VERSION 5.7 ;
  NOWIREEXTENSIONATPIN ON ;
  DIVIDERCHAR "/" ;
  BUSBITCHARS "[]" ;
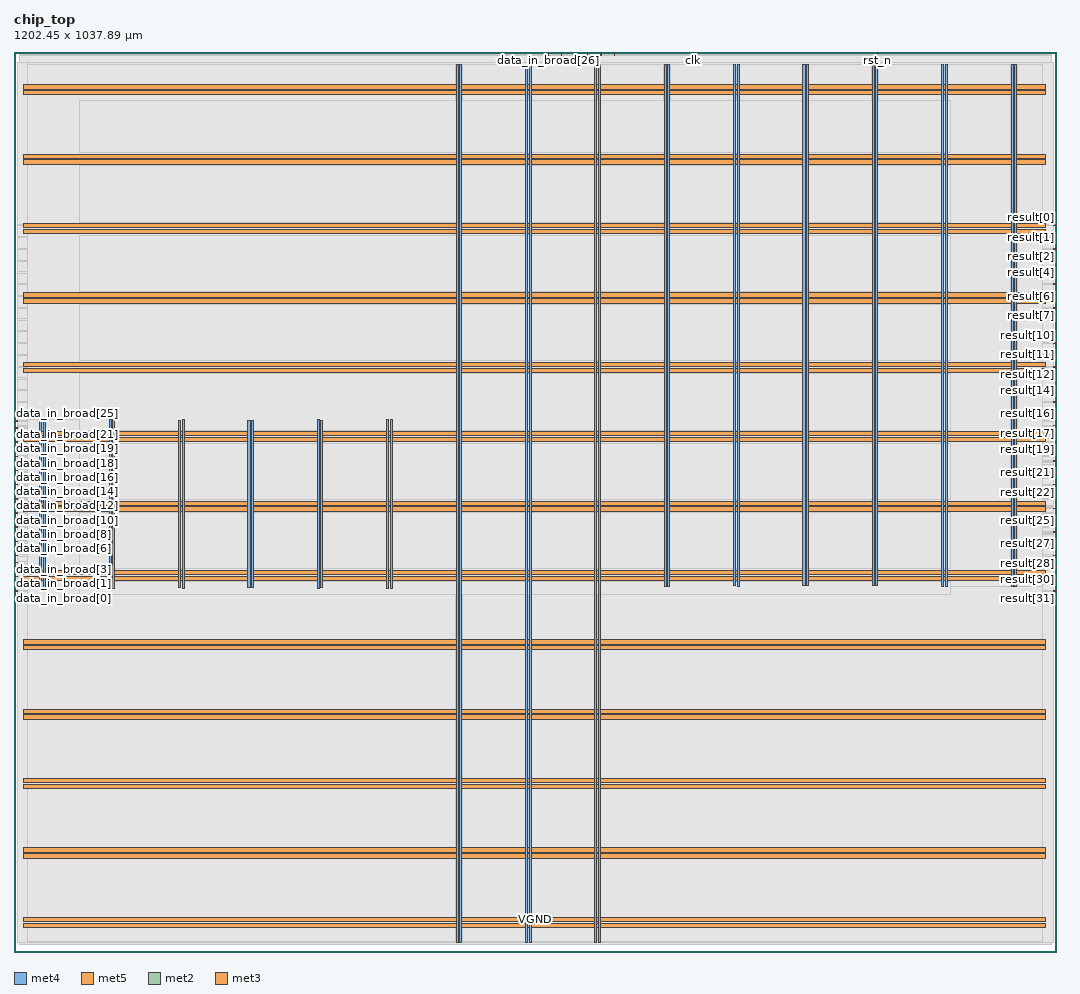
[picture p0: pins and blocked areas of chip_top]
MACRO chip_top
  CLASS BLOCK ;
  FOREIGN chip_top ;
  ORIGIN 0.000 0.000 ;
  SIZE 1202.450 BY 1037.890 ;
  PIN VGND
    DIRECTION INOUT ;
    USE GROUND ;
    PORT
      LAYER met4 ;
        RECT 33.940 419.520 36.340 614.120 ;
    END
    PORT
      LAYER met4 ;
        RECT 113.940 419.520 116.340 614.120 ;
    END
    PORT
      LAYER met4 ;
        RECT 193.940 419.520 196.340 614.120 ;
    END
    PORT
      LAYER met4 ;
        RECT 273.940 420.140 276.340 613.500 ;
    END
    PORT
      LAYER met4 ;
        RECT 353.940 420.140 356.340 613.500 ;
    END
    PORT
      LAYER met4 ;
        RECT 433.940 419.520 436.340 614.120 ;
    END
    PORT
      LAYER met4 ;
        RECT 513.940 10.640 516.340 1022.960 ;
    END
    PORT
      LAYER met4 ;
        RECT 593.940 10.640 596.340 1022.960 ;
    END
    PORT
      LAYER met4 ;
        RECT 673.940 10.640 676.340 1022.960 ;
    END
    PORT
      LAYER met4 ;
        RECT 753.940 421.520 756.340 1022.960 ;
    END
    PORT
      LAYER met4 ;
        RECT 833.940 421.520 836.340 1022.960 ;
    END
    PORT
      LAYER met4 ;
        RECT 913.940 422.140 916.340 1022.960 ;
    END
    PORT
      LAYER met4 ;
        RECT 993.940 422.140 996.340 1022.960 ;
    END
    PORT
      LAYER met4 ;
        RECT 1073.940 421.520 1076.340 1022.960 ;
    END
    PORT
      LAYER met4 ;
        RECT 1153.940 421.520 1156.340 1022.960 ;
    END
    PORT
      LAYER met5 ;
        RECT 10.800 35.080 1189.800 40.080 ;
    END
    PORT
      LAYER met5 ;
        RECT 10.800 115.080 1189.800 120.080 ;
    END
    PORT
      LAYER met5 ;
        RECT 10.800 195.080 1189.800 200.080 ;
    END
    PORT
      LAYER met5 ;
        RECT 10.800 275.080 1189.800 280.080 ;
    END
    PORT
      LAYER met5 ;
        RECT 10.800 355.080 1189.800 360.080 ;
    END
    PORT
      LAYER met5 ;
        RECT 10.800 435.080 1189.800 440.080 ;
    END
    PORT
      LAYER met5 ;
        RECT 10.800 515.080 1189.800 520.080 ;
    END
    PORT
      LAYER met5 ;
        RECT 10.800 595.080 1189.800 600.080 ;
    END
    PORT
      LAYER met5 ;
        RECT 10.800 675.080 1189.800 680.080 ;
    END
    PORT
      LAYER met5 ;
        RECT 10.800 755.080 1189.800 760.080 ;
    END
    PORT
      LAYER met5 ;
        RECT 10.800 835.080 1189.800 840.080 ;
    END
    PORT
      LAYER met5 ;
        RECT 10.800 915.080 1189.800 920.080 ;
    END
    PORT
      LAYER met5 ;
        RECT 10.800 995.080 1189.800 1000.080 ;
    END
  END VGND
  PIN VPWR
    DIRECTION INOUT ;
    USE POWER ;
    PORT
      LAYER met4 ;
        RECT 29.840 419.520 32.240 614.120 ;
    END
    PORT
      LAYER met4 ;
        RECT 109.840 419.520 112.240 614.120 ;
    END
    PORT
      LAYER met4 ;
        RECT 189.840 420.140 192.240 613.500 ;
    END
    PORT
      LAYER met4 ;
        RECT 269.840 420.140 272.240 613.500 ;
    END
    PORT
      LAYER met4 ;
        RECT 349.840 419.520 352.240 614.120 ;
    END
    PORT
      LAYER met4 ;
        RECT 429.840 419.520 432.240 614.120 ;
    END
    PORT
      LAYER met4 ;
        RECT 509.840 10.640 512.240 1022.960 ;
    END
    PORT
      LAYER met4 ;
        RECT 589.840 10.640 592.240 1022.960 ;
    END
    PORT
      LAYER met4 ;
        RECT 669.840 10.640 672.240 1022.960 ;
    END
    PORT
      LAYER met4 ;
        RECT 749.840 421.360 752.240 1022.960 ;
    END
    PORT
      LAYER met4 ;
        RECT 829.840 422.140 832.240 1022.960 ;
    END
    PORT
      LAYER met4 ;
        RECT 909.840 422.140 912.240 1022.960 ;
    END
    PORT
      LAYER met4 ;
        RECT 989.840 422.140 992.240 1022.960 ;
    END
    PORT
      LAYER met4 ;
        RECT 1069.840 421.360 1072.240 1022.960 ;
    END
    PORT
      LAYER met4 ;
        RECT 1149.840 421.360 1152.240 1022.960 ;
    END
    PORT
      LAYER met5 ;
        RECT 10.800 28.380 1189.800 33.380 ;
    END
    PORT
      LAYER met5 ;
        RECT 10.800 108.380 1189.800 113.380 ;
    END
    PORT
      LAYER met5 ;
        RECT 10.800 188.380 1189.800 193.380 ;
    END
    PORT
      LAYER met5 ;
        RECT 10.800 268.380 1189.800 273.380 ;
    END
    PORT
      LAYER met5 ;
        RECT 10.800 348.380 1189.800 353.380 ;
    END
    PORT
      LAYER met5 ;
        RECT 10.800 428.380 1189.800 433.380 ;
    END
    PORT
      LAYER met5 ;
        RECT 10.800 508.380 1189.800 513.380 ;
    END
    PORT
      LAYER met5 ;
        RECT 10.800 588.380 1189.800 593.380 ;
    END
    PORT
      LAYER met5 ;
        RECT 10.800 668.380 1189.800 673.380 ;
    END
    PORT
      LAYER met5 ;
        RECT 10.800 748.380 1189.800 753.380 ;
    END
    PORT
      LAYER met5 ;
        RECT 10.800 828.380 1189.800 833.380 ;
    END
    PORT
      LAYER met5 ;
        RECT 10.800 908.380 1189.800 913.380 ;
    END
    PORT
      LAYER met5 ;
        RECT 10.800 988.380 1189.800 993.380 ;
    END
  END VPWR
  PIN clk
    DIRECTION INPUT ;
    USE SIGNAL ;
    ANTENNAGATEAREA 1.286700 ;
    ANTENNADIFFAREA 0.434700 ;
    PORT
      LAYER met2 ;
        RECT 783.010 1033.890 783.290 1037.890 ;
    END
  END clk
  PIN data_in_broad[0]
    DIRECTION INPUT ;
    USE SIGNAL ;
    ANTENNAGATEAREA 0.631200 ;
    ANTENNADIFFAREA 0.434700 ;
    PORT
      LAYER met3 ;
        RECT 0.000 416.200 4.000 416.800 ;
    END
  END data_in_broad[0]
  PIN data_in_broad[10]
    DIRECTION INPUT ;
    USE SIGNAL ;
    ANTENNAGATEAREA 0.631200 ;
    ANTENNADIFFAREA 0.434700 ;
    PORT
      LAYER met3 ;
        RECT 0.000 497.800 4.000 498.400 ;
    END
  END data_in_broad[10]
  PIN data_in_broad[11]
    DIRECTION INPUT ;
    USE SIGNAL ;
    ANTENNAGATEAREA 0.631200 ;
    ANTENNADIFFAREA 0.434700 ;
    PORT
      LAYER met3 ;
        RECT 0.000 505.960 4.000 506.560 ;
    END
  END data_in_broad[11]
  PIN data_in_broad[12]
    DIRECTION INPUT ;
    USE SIGNAL ;
    ANTENNAGATEAREA 0.631200 ;
    ANTENNADIFFAREA 0.434700 ;
    PORT
      LAYER met3 ;
        RECT 0.000 514.120 4.000 514.720 ;
    END
  END data_in_broad[12]
  PIN data_in_broad[13]
    DIRECTION INPUT ;
    USE SIGNAL ;
    ANTENNAGATEAREA 0.631200 ;
    ANTENNADIFFAREA 0.434700 ;
    PORT
      LAYER met3 ;
        RECT 0.000 522.280 4.000 522.880 ;
    END
  END data_in_broad[13]
  PIN data_in_broad[14]
    DIRECTION INPUT ;
    USE SIGNAL ;
    ANTENNAGATEAREA 0.631200 ;
    ANTENNADIFFAREA 0.434700 ;
    PORT
      LAYER met3 ;
        RECT 0.000 530.440 4.000 531.040 ;
    END
  END data_in_broad[14]
  PIN data_in_broad[15]
    DIRECTION INPUT ;
    USE SIGNAL ;
    ANTENNAGATEAREA 0.631200 ;
    ANTENNADIFFAREA 0.434700 ;
    PORT
      LAYER met3 ;
        RECT 0.000 538.600 4.000 539.200 ;
    END
  END data_in_broad[15]
  PIN data_in_broad[16]
    DIRECTION INPUT ;
    USE SIGNAL ;
    ANTENNAGATEAREA 0.631200 ;
    ANTENNADIFFAREA 0.434700 ;
    PORT
      LAYER met3 ;
        RECT 0.000 546.760 4.000 547.360 ;
    END
  END data_in_broad[16]
  PIN data_in_broad[17]
    DIRECTION INPUT ;
    USE SIGNAL ;
    ANTENNAGATEAREA 0.631200 ;
    ANTENNADIFFAREA 0.434700 ;
    PORT
      LAYER met3 ;
        RECT 0.000 554.920 4.000 555.520 ;
    END
  END data_in_broad[17]
  PIN data_in_broad[18]
    DIRECTION INPUT ;
    USE SIGNAL ;
    ANTENNAGATEAREA 0.631200 ;
    ANTENNADIFFAREA 0.434700 ;
    PORT
      LAYER met3 ;
        RECT 0.000 563.080 4.000 563.680 ;
    END
  END data_in_broad[18]
  PIN data_in_broad[19]
    DIRECTION INPUT ;
    USE SIGNAL ;
    ANTENNAGATEAREA 0.631200 ;
    ANTENNADIFFAREA 0.434700 ;
    PORT
      LAYER met3 ;
        RECT 0.000 571.240 4.000 571.840 ;
    END
  END data_in_broad[19]
  PIN data_in_broad[1]
    DIRECTION INPUT ;
    USE SIGNAL ;
    ANTENNAGATEAREA 0.631200 ;
    ANTENNADIFFAREA 0.434700 ;
    PORT
      LAYER met3 ;
        RECT 0.000 424.360 4.000 424.960 ;
    END
  END data_in_broad[1]
  PIN data_in_broad[20]
    DIRECTION INPUT ;
    USE SIGNAL ;
    ANTENNAGATEAREA 0.631200 ;
    ANTENNADIFFAREA 0.434700 ;
    PORT
      LAYER met3 ;
        RECT 0.000 579.400 4.000 580.000 ;
    END
  END data_in_broad[20]
  PIN data_in_broad[21]
    DIRECTION INPUT ;
    USE SIGNAL ;
    ANTENNAGATEAREA 0.631200 ;
    ANTENNADIFFAREA 0.434700 ;
    PORT
      LAYER met3 ;
        RECT 0.000 587.560 4.000 588.160 ;
    END
  END data_in_broad[21]
  PIN data_in_broad[22]
    DIRECTION INPUT ;
    USE SIGNAL ;
    ANTENNAGATEAREA 0.631200 ;
    ANTENNADIFFAREA 0.434700 ;
    PORT
      LAYER met3 ;
        RECT 0.000 595.720 4.000 596.320 ;
    END
  END data_in_broad[22]
  PIN data_in_broad[23]
    DIRECTION INPUT ;
    USE SIGNAL ;
    ANTENNAGATEAREA 0.631200 ;
    ANTENNADIFFAREA 0.434700 ;
    PORT
      LAYER met3 ;
        RECT 0.000 603.880 4.000 604.480 ;
    END
  END data_in_broad[23]
  PIN data_in_broad[24]
    DIRECTION INPUT ;
    USE SIGNAL ;
    ANTENNAGATEAREA 0.631200 ;
    ANTENNADIFFAREA 0.434700 ;
    PORT
      LAYER met3 ;
        RECT 0.000 612.040 4.000 612.640 ;
    END
  END data_in_broad[24]
  PIN data_in_broad[25]
    DIRECTION INPUT ;
    USE SIGNAL ;
    ANTENNAGATEAREA 0.631200 ;
    ANTENNADIFFAREA 0.434700 ;
    PORT
      LAYER met3 ;
        RECT 0.000 620.200 4.000 620.800 ;
    END
  END data_in_broad[25]
  PIN data_in_broad[26]
    DIRECTION INPUT ;
    USE SIGNAL ;
    ANTENNAGATEAREA 0.593700 ;
    ANTENNADIFFAREA 0.434700 ;
    PORT
      LAYER met2 ;
        RECT 616.030 1033.890 616.310 1037.890 ;
    END
  END data_in_broad[26]
  PIN data_in_broad[27]
    DIRECTION INPUT ;
    USE SIGNAL ;
    ANTENNAGATEAREA 0.647700 ;
    ANTENNADIFFAREA 0.434700 ;
    PORT
      LAYER met2 ;
        RECT 631.210 1033.890 631.490 1037.890 ;
    END
  END data_in_broad[27]
  PIN data_in_broad[28]
    DIRECTION INPUT ;
    USE SIGNAL ;
    ANTENNAGATEAREA 0.647700 ;
    ANTENNADIFFAREA 0.434700 ;
    PORT
      LAYER met2 ;
        RECT 646.390 1033.890 646.670 1037.890 ;
    END
  END data_in_broad[28]
  PIN data_in_broad[29]
    DIRECTION INPUT ;
    USE SIGNAL ;
    ANTENNAGATEAREA 0.647700 ;
    ANTENNADIFFAREA 0.434700 ;
    PORT
      LAYER met2 ;
        RECT 661.570 1033.890 661.850 1037.890 ;
    END
  END data_in_broad[29]
  PIN data_in_broad[2]
    DIRECTION INPUT ;
    USE SIGNAL ;
    ANTENNAGATEAREA 0.631200 ;
    ANTENNADIFFAREA 0.434700 ;
    PORT
      LAYER met3 ;
        RECT 0.000 432.520 4.000 433.120 ;
    END
  END data_in_broad[2]
  PIN data_in_broad[30]
    DIRECTION INPUT ;
    USE SIGNAL ;
    ANTENNAGATEAREA 0.647700 ;
    ANTENNADIFFAREA 0.434700 ;
    PORT
      LAYER met2 ;
        RECT 676.750 1033.890 677.030 1037.890 ;
    END
  END data_in_broad[30]
  PIN data_in_broad[31]
    DIRECTION INPUT ;
    USE SIGNAL ;
    ANTENNAGATEAREA 0.647700 ;
    ANTENNADIFFAREA 0.434700 ;
    PORT
      LAYER met2 ;
        RECT 691.930 1033.890 692.210 1037.890 ;
    END
  END data_in_broad[31]
  PIN data_in_broad[3]
    DIRECTION INPUT ;
    USE SIGNAL ;
    ANTENNAGATEAREA 0.631200 ;
    ANTENNADIFFAREA 0.434700 ;
    PORT
      LAYER met3 ;
        RECT 0.000 440.680 4.000 441.280 ;
    END
  END data_in_broad[3]
  PIN data_in_broad[4]
    DIRECTION INPUT ;
    USE SIGNAL ;
    ANTENNAGATEAREA 0.631200 ;
    ANTENNADIFFAREA 0.434700 ;
    PORT
      LAYER met3 ;
        RECT 0.000 448.840 4.000 449.440 ;
    END
  END data_in_broad[4]
  PIN data_in_broad[5]
    DIRECTION INPUT ;
    USE SIGNAL ;
    ANTENNAGATEAREA 0.631200 ;
    ANTENNADIFFAREA 0.434700 ;
    PORT
      LAYER met3 ;
        RECT 0.000 457.000 4.000 457.600 ;
    END
  END data_in_broad[5]
  PIN data_in_broad[6]
    DIRECTION INPUT ;
    USE SIGNAL ;
    ANTENNAGATEAREA 0.631200 ;
    ANTENNADIFFAREA 0.434700 ;
    PORT
      LAYER met3 ;
        RECT 0.000 465.160 4.000 465.760 ;
    END
  END data_in_broad[6]
  PIN data_in_broad[7]
    DIRECTION INPUT ;
    USE SIGNAL ;
    ANTENNAGATEAREA 0.631200 ;
    ANTENNADIFFAREA 0.434700 ;
    PORT
      LAYER met3 ;
        RECT 0.000 473.320 4.000 473.920 ;
    END
  END data_in_broad[7]
  PIN data_in_broad[8]
    DIRECTION INPUT ;
    USE SIGNAL ;
    ANTENNAGATEAREA 0.631200 ;
    ANTENNADIFFAREA 0.434700 ;
    PORT
      LAYER met3 ;
        RECT 0.000 481.480 4.000 482.080 ;
    END
  END data_in_broad[8]
  PIN data_in_broad[9]
    DIRECTION INPUT ;
    USE SIGNAL ;
    ANTENNAGATEAREA 0.631200 ;
    ANTENNADIFFAREA 0.434700 ;
    PORT
      LAYER met3 ;
        RECT 0.000 489.640 4.000 490.240 ;
    END
  END data_in_broad[9]
  PIN result[0]
    DIRECTION OUTPUT TRISTATE ;
    USE SIGNAL ;
    ANTENNADIFFAREA 1.782000 ;
    PORT
      LAYER met3 ;
        RECT 1198.450 837.800 1202.450 838.400 ;
    END
  END result[0]
  PIN result[10]
    DIRECTION OUTPUT TRISTATE ;
    USE SIGNAL ;
    ANTENNADIFFAREA 1.782000 ;
    PORT
      LAYER met3 ;
        RECT 1198.450 701.800 1202.450 702.400 ;
    END
  END result[10]
  PIN result[11]
    DIRECTION OUTPUT TRISTATE ;
    USE SIGNAL ;
    ANTENNADIFFAREA 1.782000 ;
    PORT
      LAYER met3 ;
        RECT 1198.450 688.200 1202.450 688.800 ;
    END
  END result[11]
  PIN result[12]
    DIRECTION OUTPUT TRISTATE ;
    USE SIGNAL ;
    ANTENNADIFFAREA 1.782000 ;
    PORT
      LAYER met3 ;
        RECT 1198.450 674.600 1202.450 675.200 ;
    END
  END result[12]
  PIN result[13]
    DIRECTION OUTPUT TRISTATE ;
    USE SIGNAL ;
    ANTENNADIFFAREA 1.782000 ;
    PORT
      LAYER met3 ;
        RECT 1198.450 661.000 1202.450 661.600 ;
    END
  END result[13]
  PIN result[14]
    DIRECTION OUTPUT TRISTATE ;
    USE SIGNAL ;
    ANTENNADIFFAREA 1.782000 ;
    PORT
      LAYER met3 ;
        RECT 1198.450 647.400 1202.450 648.000 ;
    END
  END result[14]
  PIN result[15]
    DIRECTION OUTPUT TRISTATE ;
    USE SIGNAL ;
    ANTENNADIFFAREA 1.782000 ;
    PORT
      LAYER met3 ;
        RECT 1198.450 633.800 1202.450 634.400 ;
    END
  END result[15]
  PIN result[16]
    DIRECTION OUTPUT TRISTATE ;
    USE SIGNAL ;
    ANTENNADIFFAREA 1.782000 ;
    PORT
      LAYER met3 ;
        RECT 1198.450 620.200 1202.450 620.800 ;
    END
  END result[16]
  PIN result[17]
    DIRECTION OUTPUT TRISTATE ;
    USE SIGNAL ;
    ANTENNADIFFAREA 1.782000 ;
    PORT
      LAYER met3 ;
        RECT 1198.450 606.600 1202.450 607.200 ;
    END
  END result[17]
  PIN result[18]
    DIRECTION OUTPUT TRISTATE ;
    USE SIGNAL ;
    ANTENNADIFFAREA 1.782000 ;
    PORT
      LAYER met3 ;
        RECT 1198.450 593.000 1202.450 593.600 ;
    END
  END result[18]
  PIN result[19]
    DIRECTION OUTPUT TRISTATE ;
    USE SIGNAL ;
    ANTENNADIFFAREA 1.782000 ;
    PORT
      LAYER met3 ;
        RECT 1198.450 579.400 1202.450 580.000 ;
    END
  END result[19]
  PIN result[1]
    DIRECTION OUTPUT TRISTATE ;
    USE SIGNAL ;
    ANTENNADIFFAREA 1.782000 ;
    PORT
      LAYER met3 ;
        RECT 1198.450 824.200 1202.450 824.800 ;
    END
  END result[1]
  PIN result[20]
    DIRECTION OUTPUT TRISTATE ;
    USE SIGNAL ;
    ANTENNADIFFAREA 1.782000 ;
    PORT
      LAYER met3 ;
        RECT 1198.450 565.800 1202.450 566.400 ;
    END
  END result[20]
  PIN result[21]
    DIRECTION OUTPUT TRISTATE ;
    USE SIGNAL ;
    ANTENNADIFFAREA 1.782000 ;
    PORT
      LAYER met3 ;
        RECT 1198.450 552.200 1202.450 552.800 ;
    END
  END result[21]
  PIN result[22]
    DIRECTION OUTPUT TRISTATE ;
    USE SIGNAL ;
    ANTENNADIFFAREA 1.782000 ;
    PORT
      LAYER met3 ;
        RECT 1198.450 538.600 1202.450 539.200 ;
    END
  END result[22]
  PIN result[23]
    DIRECTION OUTPUT TRISTATE ;
    USE SIGNAL ;
    ANTENNADIFFAREA 1.782000 ;
    PORT
      LAYER met3 ;
        RECT 1198.450 525.000 1202.450 525.600 ;
    END
  END result[23]
  PIN result[24]
    DIRECTION OUTPUT TRISTATE ;
    USE SIGNAL ;
    ANTENNADIFFAREA 1.782000 ;
    PORT
      LAYER met3 ;
        RECT 1198.450 511.400 1202.450 512.000 ;
    END
  END result[24]
  PIN result[25]
    DIRECTION OUTPUT TRISTATE ;
    USE SIGNAL ;
    ANTENNADIFFAREA 1.782000 ;
    PORT
      LAYER met3 ;
        RECT 1198.450 497.800 1202.450 498.400 ;
    END
  END result[25]
  PIN result[26]
    DIRECTION OUTPUT TRISTATE ;
    USE SIGNAL ;
    ANTENNADIFFAREA 1.782000 ;
    PORT
      LAYER met3 ;
        RECT 1198.450 484.200 1202.450 484.800 ;
    END
  END result[26]
  PIN result[27]
    DIRECTION OUTPUT TRISTATE ;
    USE SIGNAL ;
    ANTENNADIFFAREA 1.782000 ;
    PORT
      LAYER met3 ;
        RECT 1198.450 470.600 1202.450 471.200 ;
    END
  END result[27]
  PIN result[28]
    DIRECTION OUTPUT TRISTATE ;
    USE SIGNAL ;
    ANTENNADIFFAREA 1.782000 ;
    PORT
      LAYER met3 ;
        RECT 1198.450 457.000 1202.450 457.600 ;
    END
  END result[28]
  PIN result[29]
    DIRECTION OUTPUT TRISTATE ;
    USE SIGNAL ;
    ANTENNADIFFAREA 1.782000 ;
    PORT
      LAYER met3 ;
        RECT 1198.450 443.400 1202.450 444.000 ;
    END
  END result[29]
  PIN result[2]
    DIRECTION OUTPUT TRISTATE ;
    USE SIGNAL ;
    ANTENNADIFFAREA 1.782000 ;
    PORT
      LAYER met3 ;
        RECT 1198.450 810.600 1202.450 811.200 ;
    END
  END result[2]
  PIN result[30]
    DIRECTION OUTPUT TRISTATE ;
    USE SIGNAL ;
    ANTENNADIFFAREA 1.782000 ;
    PORT
      LAYER met3 ;
        RECT 1198.450 429.800 1202.450 430.400 ;
    END
  END result[30]
  PIN result[31]
    DIRECTION OUTPUT TRISTATE ;
    USE SIGNAL ;
    ANTENNADIFFAREA 1.782000 ;
    PORT
      LAYER met3 ;
        RECT 1198.450 416.200 1202.450 416.800 ;
    END
  END result[31]
  PIN result[3]
    DIRECTION OUTPUT TRISTATE ;
    USE SIGNAL ;
    ANTENNADIFFAREA 1.782000 ;
    PORT
      LAYER met3 ;
        RECT 1198.450 797.000 1202.450 797.600 ;
    END
  END result[3]
  PIN result[4]
    DIRECTION OUTPUT TRISTATE ;
    USE SIGNAL ;
    ANTENNADIFFAREA 1.782000 ;
    PORT
      LAYER met3 ;
        RECT 1198.450 783.400 1202.450 784.000 ;
    END
  END result[4]
  PIN result[5]
    DIRECTION OUTPUT TRISTATE ;
    USE SIGNAL ;
    ANTENNADIFFAREA 1.782000 ;
    PORT
      LAYER met3 ;
        RECT 1198.450 769.800 1202.450 770.400 ;
    END
  END result[5]
  PIN result[6]
    DIRECTION OUTPUT TRISTATE ;
    USE SIGNAL ;
    ANTENNADIFFAREA 1.782000 ;
    PORT
      LAYER met3 ;
        RECT 1198.450 756.200 1202.450 756.800 ;
    END
  END result[6]
  PIN result[7]
    DIRECTION OUTPUT TRISTATE ;
    USE SIGNAL ;
    ANTENNADIFFAREA 1.782000 ;
    PORT
      LAYER met3 ;
        RECT 1198.450 742.600 1202.450 743.200 ;
    END
  END result[7]
  PIN result[8]
    DIRECTION OUTPUT TRISTATE ;
    USE SIGNAL ;
    ANTENNADIFFAREA 1.782000 ;
    PORT
      LAYER met3 ;
        RECT 1198.450 729.000 1202.450 729.600 ;
    END
  END result[8]
  PIN result[9]
    DIRECTION OUTPUT TRISTATE ;
    USE SIGNAL ;
    ANTENNADIFFAREA 1.782000 ;
    PORT
      LAYER met3 ;
        RECT 1198.450 715.400 1202.450 716.000 ;
    END
  END result[9]
  PIN rst_n
    DIRECTION INPUT ;
    USE SIGNAL ;
    ANTENNAGATEAREA 0.860700 ;
    ANTENNADIFFAREA 0.434700 ;
    PORT
      LAYER met2 ;
        RECT 995.530 1033.890 995.810 1037.890 ;
    END
  END rst_n
  OBS
      LAYER li1 ;
        RECT 11.040 10.795 1189.560 1022.805 ;
      LAYER met1 ;
        RECT 6.510 8.880 1196.390 1023.700 ;
      LAYER met2 ;
        RECT 6.530 1033.610 615.750 1034.690 ;
        RECT 616.590 1033.610 630.930 1034.690 ;
        RECT 631.770 1033.610 646.110 1034.690 ;
        RECT 646.950 1033.610 661.290 1034.690 ;
        RECT 662.130 1033.610 676.470 1034.690 ;
        RECT 677.310 1033.610 691.650 1034.690 ;
        RECT 692.490 1033.610 782.730 1034.690 ;
        RECT 783.570 1033.610 995.250 1034.690 ;
        RECT 996.090 1033.610 1196.370 1034.690 ;
        RECT 6.530 8.850 1196.370 1033.610 ;
      LAYER met3 ;
        RECT 4.000 838.800 1198.450 1025.945 ;
        RECT 4.000 837.400 1198.050 838.800 ;
        RECT 4.000 825.200 1198.450 837.400 ;
        RECT 4.000 823.800 1198.050 825.200 ;
        RECT 4.000 811.600 1198.450 823.800 ;
        RECT 4.000 810.200 1198.050 811.600 ;
        RECT 4.000 798.000 1198.450 810.200 ;
        RECT 4.000 796.600 1198.050 798.000 ;
        RECT 4.000 784.400 1198.450 796.600 ;
        RECT 4.000 783.000 1198.050 784.400 ;
        RECT 4.000 770.800 1198.450 783.000 ;
        RECT 4.000 769.400 1198.050 770.800 ;
        RECT 4.000 757.200 1198.450 769.400 ;
        RECT 4.000 755.800 1198.050 757.200 ;
        RECT 4.000 743.600 1198.450 755.800 ;
        RECT 4.000 742.200 1198.050 743.600 ;
        RECT 4.000 730.000 1198.450 742.200 ;
        RECT 4.000 728.600 1198.050 730.000 ;
        RECT 4.000 716.400 1198.450 728.600 ;
        RECT 4.000 715.000 1198.050 716.400 ;
        RECT 4.000 702.800 1198.450 715.000 ;
        RECT 4.000 701.400 1198.050 702.800 ;
        RECT 4.000 689.200 1198.450 701.400 ;
        RECT 4.000 687.800 1198.050 689.200 ;
        RECT 4.000 675.600 1198.450 687.800 ;
        RECT 4.000 674.200 1198.050 675.600 ;
        RECT 4.000 662.000 1198.450 674.200 ;
        RECT 4.000 660.600 1198.050 662.000 ;
        RECT 4.000 648.400 1198.450 660.600 ;
        RECT 4.000 647.000 1198.050 648.400 ;
        RECT 4.000 634.800 1198.450 647.000 ;
        RECT 4.000 633.400 1198.050 634.800 ;
        RECT 4.000 621.200 1198.450 633.400 ;
        RECT 4.400 619.800 1198.050 621.200 ;
        RECT 4.000 613.040 1198.450 619.800 ;
        RECT 4.400 611.640 1198.450 613.040 ;
        RECT 4.000 607.600 1198.450 611.640 ;
        RECT 4.000 606.200 1198.050 607.600 ;
        RECT 4.000 604.880 1198.450 606.200 ;
        RECT 4.400 603.480 1198.450 604.880 ;
        RECT 4.000 596.720 1198.450 603.480 ;
        RECT 4.400 595.320 1198.450 596.720 ;
        RECT 4.000 594.000 1198.450 595.320 ;
        RECT 4.000 592.600 1198.050 594.000 ;
        RECT 4.000 588.560 1198.450 592.600 ;
        RECT 4.400 587.160 1198.450 588.560 ;
        RECT 4.000 580.400 1198.450 587.160 ;
        RECT 4.400 579.000 1198.050 580.400 ;
        RECT 4.000 572.240 1198.450 579.000 ;
        RECT 4.400 570.840 1198.450 572.240 ;
        RECT 4.000 566.800 1198.450 570.840 ;
        RECT 4.000 565.400 1198.050 566.800 ;
        RECT 4.000 564.080 1198.450 565.400 ;
        RECT 4.400 562.680 1198.450 564.080 ;
        RECT 4.000 555.920 1198.450 562.680 ;
        RECT 4.400 554.520 1198.450 555.920 ;
        RECT 4.000 553.200 1198.450 554.520 ;
        RECT 4.000 551.800 1198.050 553.200 ;
        RECT 4.000 547.760 1198.450 551.800 ;
        RECT 4.400 546.360 1198.450 547.760 ;
        RECT 4.000 539.600 1198.450 546.360 ;
        RECT 4.400 538.200 1198.050 539.600 ;
        RECT 4.000 531.440 1198.450 538.200 ;
        RECT 4.400 530.040 1198.450 531.440 ;
        RECT 4.000 526.000 1198.450 530.040 ;
        RECT 4.000 524.600 1198.050 526.000 ;
        RECT 4.000 523.280 1198.450 524.600 ;
        RECT 4.400 521.880 1198.450 523.280 ;
        RECT 4.000 515.120 1198.450 521.880 ;
        RECT 4.400 513.720 1198.450 515.120 ;
        RECT 4.000 512.400 1198.450 513.720 ;
        RECT 4.000 511.000 1198.050 512.400 ;
        RECT 4.000 506.960 1198.450 511.000 ;
        RECT 4.400 505.560 1198.450 506.960 ;
        RECT 4.000 498.800 1198.450 505.560 ;
        RECT 4.400 497.400 1198.050 498.800 ;
        RECT 4.000 490.640 1198.450 497.400 ;
        RECT 4.400 489.240 1198.450 490.640 ;
        RECT 4.000 485.200 1198.450 489.240 ;
        RECT 4.000 483.800 1198.050 485.200 ;
        RECT 4.000 482.480 1198.450 483.800 ;
        RECT 4.400 481.080 1198.450 482.480 ;
        RECT 4.000 474.320 1198.450 481.080 ;
        RECT 4.400 472.920 1198.450 474.320 ;
        RECT 4.000 471.600 1198.450 472.920 ;
        RECT 4.000 470.200 1198.050 471.600 ;
        RECT 4.000 466.160 1198.450 470.200 ;
        RECT 4.400 464.760 1198.450 466.160 ;
        RECT 4.000 458.000 1198.450 464.760 ;
        RECT 4.400 456.600 1198.050 458.000 ;
        RECT 4.000 449.840 1198.450 456.600 ;
        RECT 4.400 448.440 1198.450 449.840 ;
        RECT 4.000 444.400 1198.450 448.440 ;
        RECT 4.000 443.000 1198.050 444.400 ;
        RECT 4.000 441.680 1198.450 443.000 ;
        RECT 4.400 440.280 1198.450 441.680 ;
        RECT 4.000 433.520 1198.450 440.280 ;
        RECT 4.400 432.120 1198.450 433.520 ;
        RECT 4.000 430.800 1198.450 432.120 ;
        RECT 4.000 429.400 1198.050 430.800 ;
        RECT 4.000 425.360 1198.450 429.400 ;
        RECT 4.400 423.960 1198.450 425.360 ;
        RECT 4.000 417.200 1198.450 423.960 ;
        RECT 4.400 415.800 1198.050 417.200 ;
        RECT 4.000 10.715 1198.450 415.800 ;
      LAYER met4 ;
        RECT 15.660 1023.360 1186.505 1025.945 ;
        RECT 15.660 614.520 509.440 1023.360 ;
        RECT 15.660 419.120 29.440 614.520 ;
        RECT 32.640 419.120 33.540 614.520 ;
        RECT 36.740 419.120 109.440 614.520 ;
        RECT 112.640 419.120 113.540 614.520 ;
        RECT 116.740 613.900 193.540 614.520 ;
        RECT 116.740 419.740 189.440 613.900 ;
        RECT 192.640 419.740 193.540 613.900 ;
        RECT 116.740 419.120 193.540 419.740 ;
        RECT 196.740 613.900 349.440 614.520 ;
        RECT 196.740 419.740 269.440 613.900 ;
        RECT 272.640 419.740 273.540 613.900 ;
        RECT 276.740 419.740 349.440 613.900 ;
        RECT 196.740 419.120 349.440 419.740 ;
        RECT 352.640 613.900 429.440 614.520 ;
        RECT 352.640 419.740 353.540 613.900 ;
        RECT 356.740 419.740 429.440 613.900 ;
        RECT 352.640 419.120 429.440 419.740 ;
        RECT 432.640 419.120 433.540 614.520 ;
        RECT 436.740 419.120 509.440 614.520 ;
        RECT 15.660 12.040 509.440 419.120 ;
        RECT 512.640 12.040 513.540 1023.360 ;
        RECT 516.740 12.040 589.440 1023.360 ;
        RECT 592.640 12.040 593.540 1023.360 ;
        RECT 596.740 12.040 669.440 1023.360 ;
        RECT 672.640 12.040 673.540 1023.360 ;
        RECT 676.740 420.960 749.440 1023.360 ;
        RECT 752.640 421.120 753.540 1023.360 ;
        RECT 756.740 421.740 829.440 1023.360 ;
        RECT 832.640 421.740 833.540 1023.360 ;
        RECT 756.740 421.120 833.540 421.740 ;
        RECT 836.740 421.740 909.440 1023.360 ;
        RECT 912.640 421.740 913.540 1023.360 ;
        RECT 916.740 421.740 989.440 1023.360 ;
        RECT 992.640 421.740 993.540 1023.360 ;
        RECT 996.740 421.740 1069.440 1023.360 ;
        RECT 836.740 421.120 1069.440 421.740 ;
        RECT 752.640 420.960 1069.440 421.120 ;
        RECT 1072.640 421.120 1073.540 1023.360 ;
        RECT 1076.740 421.120 1149.440 1023.360 ;
        RECT 1072.640 420.960 1149.440 421.120 ;
        RECT 1152.640 421.120 1153.540 1023.360 ;
        RECT 1156.740 421.120 1186.505 1023.360 ;
        RECT 1152.640 420.960 1186.505 421.120 ;
        RECT 676.740 12.040 1186.505 420.960 ;
      LAYER met5 ;
        RECT 75.100 921.680 1080.420 981.700 ;
        RECT 75.100 841.680 1080.420 906.780 ;
        RECT 75.100 761.680 1080.420 826.780 ;
        RECT 75.100 681.680 1080.420 746.780 ;
        RECT 75.100 601.680 1080.420 666.780 ;
        RECT 75.100 521.680 1080.420 586.780 ;
        RECT 75.100 441.680 1080.420 506.780 ;
        RECT 75.100 412.300 1080.420 426.780 ;
  END
END chip_top
END LIBRARY

